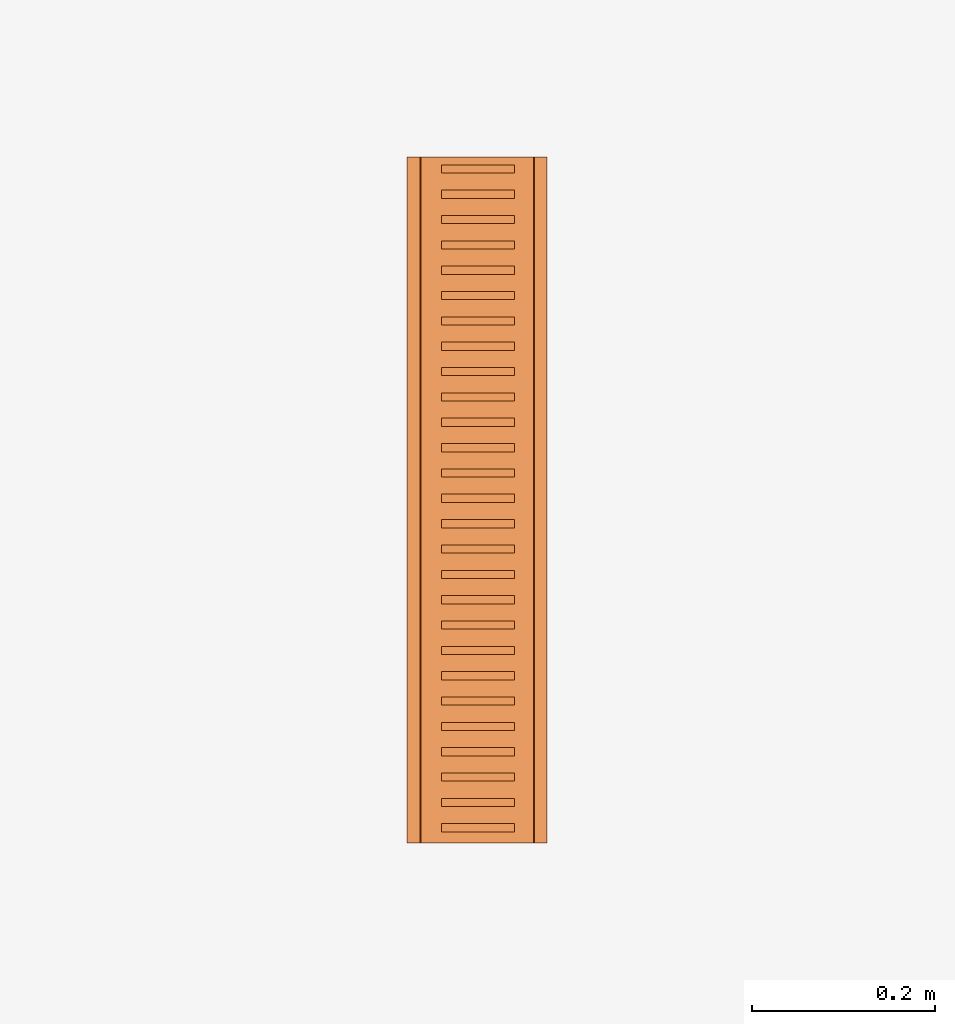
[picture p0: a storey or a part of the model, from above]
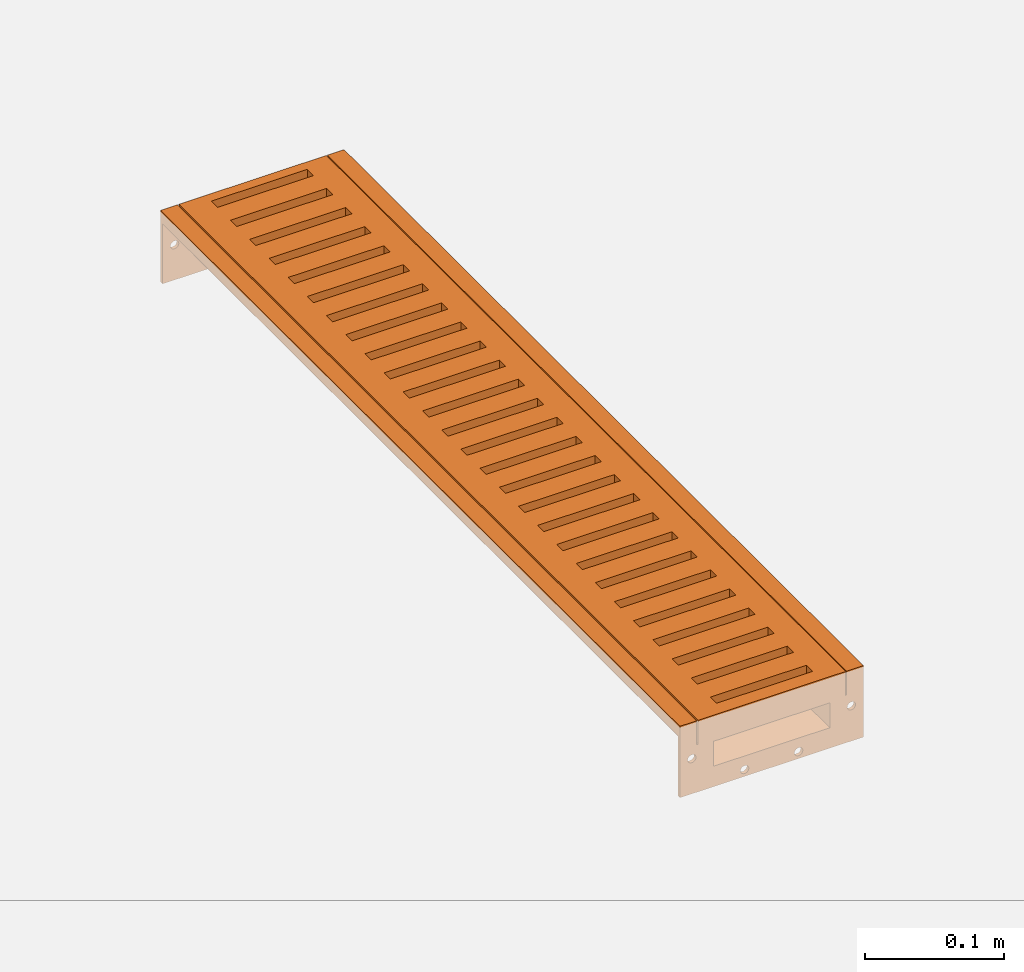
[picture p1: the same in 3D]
Properties of the parts of a building model (IFC2X3)

# File
Description: ViewDefinition [CoordinationView]
File name: Non Standard Length Channel.ifc
Time: 2014-03-20T14:48:19
Written by: Autodesk Revit 2013
Made in: 20120221_2030(x64)

# IfcProject, Project Number
LongName: Project Name; Phase: Project Status

# IfcSite, Default
RefLatitude: 42, 21, 30, 344238; RefLongitude: -71, -3, -35, -194702; RefElevation: 0 mm

# IfcBuilding
Pset_BuildingCommon - NumberOfStoreys: 1
Other - Project Address: ## Street City, State Zip; Project Name: Project Name; Project Number: Project Number; Project Issue Date: Issue Date; Client Name: Owner; Project Status: Project Status

# IfcBuildingStorey, Level 1
LongName: Level 1; Elevation: 0 mm
Constraints - Elevation Base: 0; Elevation: 0 mm
Graphics - Symbol at End 1 Default: no; Symbol at End 2 Default: yes; Symbol: M_Level Head - Circle: M_Level Head - Circle; Line Pattern: Center; Line Weight: 1; Color: 0
Identity Data - Structural: no; Name: Level 1; Building Story: yes
Dimensions - Computation Height: 0 mm

# IfcBuildingElementProxy: Non Standard Length Channel, ACO BD Deckline 125 Straight Channel:Non Standard Length Channel:Non Standard Length Channel:225886
In: Level 1
Material: Steel, Galvanized
Dimensions - Void Length: -750 mm; Length: 750 mm; Custom Void: 2250 mm; Custom Channel: 744 mm; EndCap Distance: 750 mm; Volume: 2132667 mm3; Channel Len: 1494 mm
Construction - 105251 - Endplate - Invert 1: no; 15704 - Composite Grating (Black) - 500mm Long: no; 105251 - Endplate - Invert 2: no; 105509 - C250 Perforated Grating - 1000mm Long: no; 105525 - C250 Slotted Grating - 1000mm Long: no; 105522 - A15 Slotted Grating - 500mm Long: no; 105523 - A15 Slotted Grating - 1000mm Long: no; 105508 - C250 Perforated Grating - 500mm Long: no; 105524 - C250 Slotted Grating - 500mm Long: no; 10735 - Composite Grating (White) - 500mm Long: no; Grating: yes; Standard Channel: no; Non Standard Channel: yes
Phasing - Phase Created: New Construction
Constraints - Moves With Nearby Elements: no; Level: Level: Level 1
Pset_BuildingElementProxyCommon - Reference: Non Standard Length Channel
Identity Data - Website: www.acobd.com; Manufacturer: ACO Building Drainage; E-mail Technical: abdtechnical@aco.co.uk; E-mail Sales: abdcommercial@aco.co.uk; Watermarked With: BIM Manager Premium Suite; Watermarked By: www.aco.co.uk; Watermark2: This file is water marked and users are prohibited to reproduce, adapt, distribute this information; Telephone: +44 (0)1462 816666; Fax: +44 (0)1462 851490; Address: ACO Business Centre, Caxton Road, Bedford, MK41 0LF; Watermark1: This file is the property of ACO Technologies PLC
General - Product Range: ACO Deckline 125; Product Description: ACO Deckline Level Invert Channel (Non Standard Length); Price: POA - contact ACO; Maintenance guidelines: X:\Electronic Literature\Building Drainage Literature\Deckline\Deckline 125.PDF; Channel Colour: Galvanised; NBS Specification: NBS Section Q10 Kerbs/edgings/channels/paving accessories, Clause 180 Drainage Channel Systems; Load Class: A15 - C250; Dimensions (LxWxH): (10-3000)x153x63; Seal Recycled Material Content: 0%; Installation guidelines: X:\Electronic Literature\Building Drainage Literature\Deckline\Deckline 125.PDF; Channel Material: Hot Dipped Galvanised Steel; Product Type: shallow invert surface water drainage system; Channel Recycled Material Content: 25 - 30 %; Product Standard: BS EN 1433:2002 CE marked; Product Code: N/A; Channel Recyclable: Fully recyclable; Seal Colour: Black; Seal Material: Neoprene; Seal Recyclable: Fully recyclable
Model Properties - Grating Product Code 105524: Load Class C250 - Slotted Galvanised Steel - 1000mm long - 4.7kg; Grating Product Code 105525: Load Class C250 - Slotted Galvanised Steel - 500mm long - 2.3kg; Grating Product Code 10735: Load Class C250 - Composite White - 500mm long - 1.2kg; Grating Product Code 15704: Load Class C250 - Composite Black - 500mm long - 1.2kg; Grating Product Code 105509: Load Class C250 - Perforated Galvanised Steel - 500mm long - 2.3kg; Grating Product Code 105508: Load Class C250 - Perforated Galvanised Steel - 1000mm long - 4.8kg; Grating Product Code 105523: Load Class A15 - Slotted Galvanised Steel - 500mm long - 1.0kg; Grating Product Code 105522: Load Class A15 - Slotted Galvanised Steel - 1000mm long - 2.0kg

# IfcOpeningElement: Opening
In: Level 1
Constraints - Room Bounding: yes; Related to Mass: no; Height Offset From Level: 0 mm; Level: Level: Level 1
Dimensions - Perimeter: 16000 mm; Volume: 6392771902 mm3; Area: 16000000 mm2; Thickness: 400 mm
Phasing - Phase Created: New Construction
Structural - Enable Analytical Model: no; Structural: no
Construction - Function: 0; Default Thickness: 400 mm
Analytical Properties - Thermal mass: 604440; Roughness: 1; Heat Transfer Coefficient (U): 2.615; Thermal Resistance (R): 0.382409; Absorptance: 0.1
Graphics - Coarse Scale Fill Color: 0
Materials and Finishes - Structural Material: Concrete, Broom Finish

# IfcSlab: Floor:Generic Floor - 400mm, Floor:Generic Floor - 400mm:193825
In: Level 1
PredefinedType: FLOOR; Material: Concrete, Broom Finish 400 mm
Constraints - Room Bounding: yes; Related to Mass: no; Height Offset From Level: 0 mm; Level: Level: Level 1
Dimensions - Perimeter: 16000 mm; Volume: 6392771902 mm3; Area: 16000000 mm2; Thickness: 400 mm
Phasing - Phase Created: New Construction
Structural - Enable Analytical Model: no; Structural: no
Pset_SlabCommon - Reference: Generic Floor - 400mm; IsExternal: no; LoadBearing: yes
Construction - Function: 0; Default Thickness: 400 mm
Analytical Properties - Thermal mass: 604440; Roughness: 1; Heat Transfer Coefficient (U): 2.615; Thermal Resistance (R): 0.382409; Absorptance: 0.1
Graphics - Coarse Scale Fill Color: 0
Materials and Finishes - Structural Material: Concrete, Broom Finish
